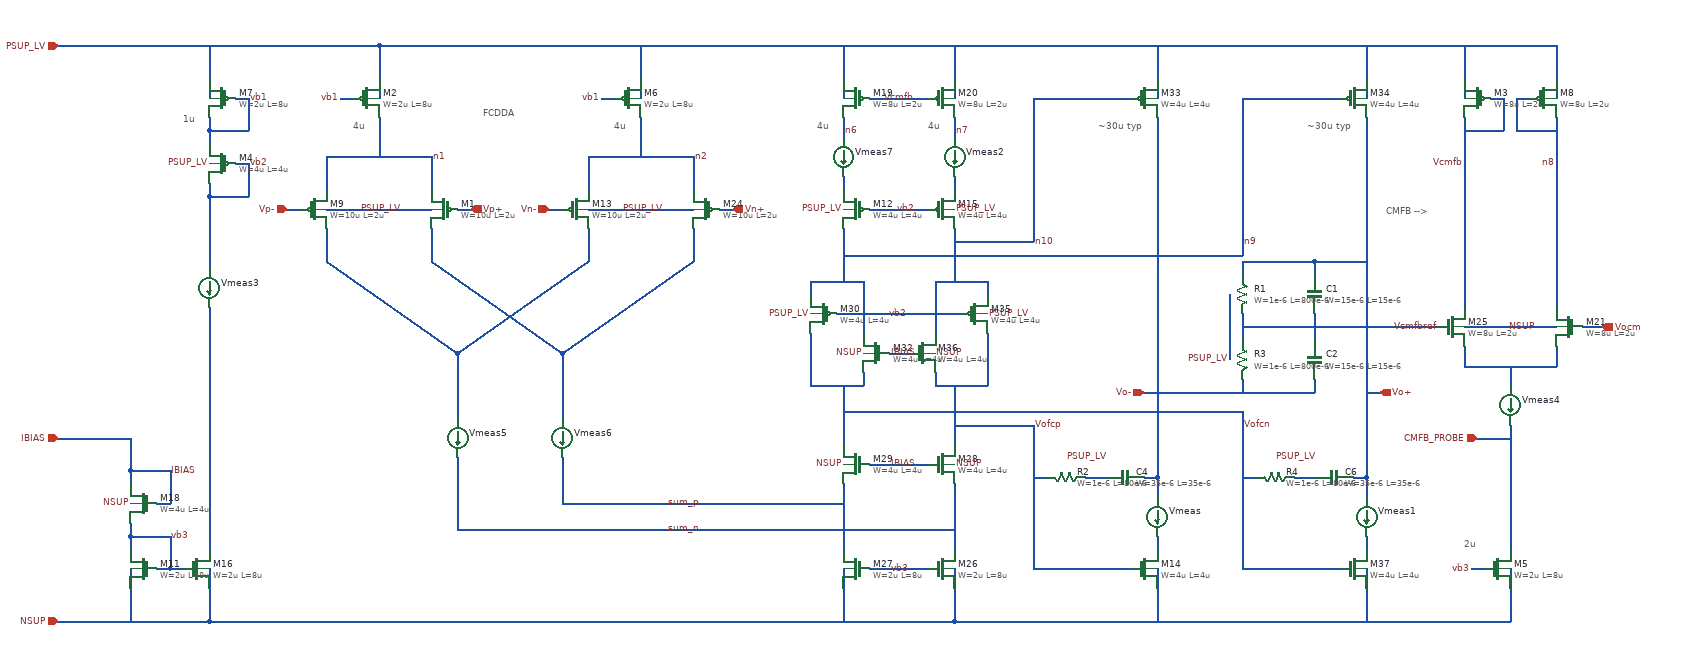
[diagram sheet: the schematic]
v {xschem version=3.4.7 file_version=1.2}
G {}
K {}
V {}
S {}
E {}
T {1u} -340 -630 0 0 0.4 0.4 {}
T {4u} -80 -620 0 0 0.4 0.4 {}
T {CMFB -->} 1500 -490 0 0 0.4 0.4 {}
T {4u} 630 -620 0 0 0.4 0.4 {}
T {4u} 800 -620 0 0 0.4 0.4 {}
T {2u} 1620 20 0 0 0.4 0.4 {}
T {FCDDA} 120 -640 0 0 0.4 0.4 {}
T {~30u typ} 1060 -620 0 0 0.4 0.4 {}
T {~30u typ} 1380 -620 0 0 0.4 0.4 {}
T {4u} 320 -620 0 0 0.4 0.4 {}
N -530 -730 -520 -730 {lab=PSUP_LV}
N -300 -680 -300 -650 {lab=PSUP_LV}
N -300 -730 -300 -680 {lab=PSUP_LV}
N -300 -600 -240 -600 {lab=vb1}
N -300 20 -300 40 {lab=#net1}
N -360 70 -340 70 {lab=vb3}
N -120 -560 -120 -510 {lab=n1}
N 40 -560 40 -510 {lab=n1}
N -40 -620 -40 -560 {lab=n1}
N -40 -730 -40 -680 {lab=PSUP_LV}
N -120 -450 -120 -400 {lab=#net2}
N 360 -680 360 -650 {lab=PSUP_LV}
N -100 -650 -80 -650 {lab=vb1}
N 300 -650 320 -650 {lab=vb1}
N 80 -480 100 -480 {lab=Vp+}
N -180 -480 -160 -480 {lab=Vp-}
N 360 -730 360 -680 {lab=PSUP_LV}
N -40 -680 -40 -650 {lab=PSUP_LV}
N -120 -560 30 -560 {lab=n1}
N 280 -560 280 -510 {lab=n2}
N 440 -560 440 -510 {lab=n2}
N 280 -560 440 -560 {lab=n2}
N 360 -620 360 -560 {lab=n2}
N 40 -450 40 -400 {lab=#net3}
N 440 -450 440 -400 {lab=#net3}
N 220 -480 240 -480 {lab=Vn-}
N 480 -480 500 -480 {lab=Vn+}
N 30 -560 40 -560 {lab=n1}
N -120 -400 80 -260 {lab=#net2}
N 80 -260 280 -400 {lab=#net2}
N 280 -480 430 -480 {lab=PSUP_LV}
N 280 -450 280 -400 {lab=#net2}
N 40 -400 240 -260 {lab=#net3}
N 240 -260 440 -400 {lab=#net3}
N 430 -480 440 -480 {lab=PSUP_LV}
N -260 -650 -240 -650 {lab=vb1}
N 710 -650 800 -650 {lab=Vcmfb}
N 710 70 800 70 {lab=vb3}
N 670 -730 670 -650 {lab=PSUP_LV}
N 840 -730 840 -650 {lab=PSUP_LV}
N -240 -650 -240 -600 {lab=vb1}
N -300 -620 -300 -600 {lab=vb1}
N -300 -500 -240 -500 {lab=vb2}
N -240 -550 -240 -500 {lab=vb2}
N -300 -520 -300 -500 {lab=vb2}
N -260 -550 -240 -550 {lab=vb2}
N -300 -600 -300 -580 {lab=vb1}
N -300 -500 -300 -450 {lab=vb2}
N 740 -90 760 -90 {lab=IBIAS}
N 710 -90 740 -90 {lab=IBIAS}
N 760 -90 800 -90 {lab=IBIAS}
N 740 -480 760 -480 {lab=vb2}
N 710 -480 740 -480 {lab=vb2}
N 760 -480 800 -480 {lab=vb2}
N 80 -100 80 -50 {lab=sum_n}
N 140 10 840 10 {lab=sum_n}
N 240 -30 610 -30 {lab=sum_p}
N 1620 -270 1620 -240 {lab=#net4}
N 1760 -270 1760 -240 {lab=#net4}
N 1620 -440 1620 -350 {lab=Vcmfb
}
N 1760 -460 1760 -400 {lab=n8}
N 1630 -300 1750 -300 {lab=NSUP}
N 1630 -240 1750 -240 {lab=#net4}
N 1660 -650 1670 -650 {lab=Vcmfb}
N 1620 -600 1670 -600 {lab=Vcmfb}
N 1710 -650 1720 -650 {lab=n8}
N 1710 -600 1760 -600 {lab=n8}
N 1670 -650 1680 -650 {lab=Vcmfb}
N 1680 -650 1680 -600 {lab=Vcmfb}
N 1670 -600 1680 -600 {lab=Vcmfb}
N 1700 -650 1710 -650 {lab=n8}
N 1700 -650 1700 -600 {lab=n8}
N 1700 -600 1710 -600 {lab=n8}
N 1620 -300 1630 -300 {lab=NSUP}
N 1750 -300 1760 -300 {lab=NSUP}
N 1620 -240 1630 -240 {lab=#net4}
N 1750 -240 1760 -240 {lab=#net4}
N 1760 -610 1760 -460 {lab=n8}
N 1620 -610 1620 -470 {lab=Vcmfb}
N 1620 -470 1620 -440 {lab=Vcmfb}
N 1760 -730 1760 -650 {lab=PSUP_LV}
N 1620 -730 1620 -650 {lab=PSUP_LV}
N 1620 -620 1620 -610 {lab=Vcmfb}
N 1760 -620 1760 -610 {lab=n8}
N 1640 -130 1690 -130 {lab=CMFB_PROBE}
N -120 -480 40 -480 {lab=PSUP_LV}
N 610 -30 670 -30 {lab=sum_p}
N -300 -450 -300 -390 {lab=vb2}
N 240 -100 240 -60 {lab=sum_p}
N 80 10 140 10 {lab=sum_n}
N 80 -20 80 10 {lab=sum_n}
N -360 20 -360 70 {lab=vb3}
N -420 20 -420 40 {lab=vb3}
N -380 70 -360 70 {lab=vb3}
N -420 20 -360 20 {lab=vb3}
N -360 -80 -360 -30 {lab=IBIAS}
N -420 -80 -420 -60 {lab=IBIAS}
N -380 -30 -360 -30 {lab=IBIAS}
N -420 -80 -360 -80 {lab=IBIAS}
N 620 -290 620 -210 {lab=Vofcn}
N 700 -220 700 -210 {lab=Vofcn}
N 700 -230 700 -220 {lab=Vofcn}
N 700 -360 700 -290 {lab=n9}
N 700 -370 700 -360 {lab=n9}
N 640 -370 700 -370 {lab=n9}
N 620 -370 620 -350 {lab=n9}
N 620 -370 640 -370 {lab=n9}
N 620 -210 640 -210 {lab=Vofcn}
N 740 -260 770 -260 {lab=IBIAS}
N 890 -290 890 -210 {lab=Vofcp}
N 810 -210 870 -210 {lab=Vofcp}
N 810 -220 810 -210 {lab=Vofcp}
N 810 -230 810 -220 {lab=Vofcp}
N 810 -360 810 -290 {lab=n10}
N 810 -370 810 -360 {lab=n10}
N 810 -370 870 -370 {lab=n10}
N 890 -370 890 -350 {lab=n10}
N 870 -370 890 -370 {lab=n10}
N 870 -210 890 -210 {lab=Vofcp}
N 640 -210 700 -210 {lab=Vofcn}
N 670 -450 670 -420 {lab=n9}
N 840 -450 840 -420 {lab=n10}
N 670 -200 670 -180 {lab=Vofcn}
N 660 -320 850 -320 {lab=vb2}
N -420 0 -420 20 {lab=vb3}
N 670 -380 670 -370 {lab=n9}
N 840 -380 840 -370 {lab=n10}
N 1150 -730 1150 -650 {lab=PSUP_LV}
N 1470 -730 1470 -650 {lab=PSUP_LV}
N 1150 70 1150 100 {lab=NSUP}
N 1470 70 1470 100 {lab=NSUP}
N 670 -180 670 -160 {lab=Vofcn}
N 670 -420 670 -380 {lab=n9}
N 840 -420 840 -380 {lab=n10}
N 840 -430 960 -430 {lab=n10}
N 960 -650 960 -430 {lab=n10}
N 1000 -650 1110 -650 {lab=n10}
N 1280 -650 1280 -430 {lab=n9}
N 1320 -650 1430 -650 {lab=n9}
N -420 -100 -420 -80 {lab=IBIAS}
N -300 0 -300 20 {lab=#net1}
N -420 100 -420 150 {lab=NSUP}
N -300 100 -300 150 {lab=NSUP}
N 840 100 840 150 {lab=NSUP}
N 840 70 840 100 {lab=NSUP}
N 670 70 670 150 {lab=NSUP}
N 670 20 670 40 {lab=sum_p}
N 840 20 840 40 {lab=sum_n}
N 240 -60 240 -40 {lab=sum_p}
N 80 -40 80 -20 {lab=sum_n}
N 670 -60 670 20 {lab=sum_p}
N 670 -160 670 -120 {lab=Vofcn}
N 840 -160 840 -120 {lab=Vofcp}
N 1150 100 1150 150 {lab=NSUP}
N 1470 100 1470 150 {lab=NSUP}
N 1470 -620 1470 -600 {lab=Vo+}
N 80 -50 80 -40 {lab=sum_n}
N 240 -40 240 -30 {lab=sum_p}
N 840 -150 960 -150 {lab=Vofcp}
N 960 -150 960 70 {lab=Vofcp}
N 1000 70 1110 70 {lab=Vofcp}
N 670 -210 670 -200 {lab=Vofcn}
N 240 -260 240 -250 {lab=#net3}
N 80 -260 80 -250 {lab=#net2}
N 1280 40 1280 70 {lab=Vofcn}
N 1320 70 1430 70 {lab=Vofcn}
N 1470 -600 1470 -590 {lab=Vo+}
N 1150 -620 1150 -610 {lab=Vo-}
N -300 70 -300 100 {lab=NSUP}
N -420 70 -420 100 {lab=NSUP}
N 670 -410 910 -410 {lab=n9}
N 840 -210 840 -160 {lab=Vofcp}
N 670 -170 910 -170 {lab=Vofcn}
N 840 150 880 150 {lab=NSUP}
N 960 70 1000 70 {lab=Vofcp}
N 910 -170 950 -170 {lab=Vofcn}
N 910 -410 950 -410 {lab=n9}
N 960 -650 1000 -650 {lab=n10}
N 1000 -410 1280 -410 {lab=n9}
N 1000 -170 1280 -170 {lab=Vofcn}
N 1280 -650 1320 -650 {lab=n9}
N 1280 70 1320 70 {lab=Vofcn}
N 1130 -200 1150 -200 {lab=Vo-}
N 1470 -200 1490 -200 {lab=Vo+}
N 1660 -730 1720 -730 {lab=PSUP_LV}
N 1650 -730 1660 -730 {lab=PSUP_LV}
N 1800 -300 1830 -300 {lab=Vocm}
N 1720 -730 1760 -730 {lab=PSUP_LV}
N 1150 -200 1190 -200 {lab=Vo-}
N 880 150 920 150 {lab=NSUP}
N 1690 20 1690 40 {lab=CMFB_PROBE}
N 1630 70 1650 70 {lab=vb3}
N 1690 -80 1690 -60 {lab=CMFB_PROBE}
N 1690 0 1690 20 {lab=CMFB_PROBE}
N 1690 100 1690 150 {lab=NSUP}
N 1690 70 1690 100 {lab=NSUP}
N 1690 -140 1690 -80 {lab=CMFB_PROBE}
N 1400 -400 1470 -400 {lab=Vo+}
N 1280 -170 1280 40 {lab=Vofcn}
N 1280 -430 1280 -410 {lab=n9}
N 1760 -400 1760 -330 {lab=n8}
N 1620 -350 1620 -330 {lab=Vcmfb}
N 1560 -300 1580 -300 {lab=Vcmfbref}
N 1690 -240 1690 -230 {lab=#net4}
N 1330 -300 1560 -300 {lab=Vcmfbref}
N 970 150 1690 150 {lab=NSUP}
N 1570 -730 1650 -730 {lab=PSUP_LV}
N 840 0 840 20 {lab=sum_n}
N 840 -60 840 0 {lab=sum_n}
N 920 150 970 150 {lab=NSUP}
N 950 -170 1000 -170 {lab=Vofcn}
N 1190 -200 1240 -200 {lab=Vo-}
N 950 -410 1000 -410 {lab=n9}
N 1150 20 1150 40 {lab=#net5}
N 1130 -70 1150 -70 {lab=Vo-}
N 1450 -70 1470 -70 {lab=Vo+}
N 690 150 840 150 {lab=NSUP}
N 1280 -310 1280 -280 {lab=Vcmfbref}
N 1280 -320 1280 -310 {lab=Vcmfbref}
N 1280 -300 1310 -300 {lab=Vcmfbref}
N 1390 -320 1390 -280 {lab=Vcmfbref}
N 1390 -320 1390 -300 {lab=Vcmfbref}
N 1280 -400 1280 -380 {lab=Vo+}
N 1290 -400 1390 -400 {lab=Vo+}
N 1390 -400 1390 -380 {lab=Vo+}
N 1390 -220 1390 -200 {lab=Vo-}
N 1280 -220 1280 -200 {lab=Vo-}
N 1260 -350 1260 -250 {lab=PSUP_LV}
N 1310 -300 1320 -300 {lab=Vcmfbref}
N 1280 -400 1290 -400 {lab=Vo+}
N 1240 -200 1390 -200 {lab=Vo-}
N 1320 -300 1330 -300 {lab=Vcmfbref}
N 1390 -400 1400 -400 {lab=Vo+}
N -300 -200 -300 0 {lab=#net1}
N -460 -130 -420 -130 {lab=IBIAS}
N -500 150 -300 150 {lab=NSUP}
N -40 -730 1570 -730 {lab=PSUP_LV}
N 1150 -610 1150 -70 {lab=Vo-}
N 1150 -70 1150 -40 {lab=Vo-}
N 1470 -590 1470 -70 {lab=Vo+}
N 1470 20 1470 40 {lab=#net6}
N 1470 -70 1470 -40 {lab=Vo+}
N -420 -130 -420 -100 {lab=IBIAS}
N -530 -130 -460 -130 {lab=IBIAS}
N -530 150 -500 150 {lab=NSUP}
N -520 -730 -260 -730 {lab=PSUP_LV}
N -260 -730 -40 -730 {lab=PSUP_LV}
N -300 150 690 150 {lab=NSUP}
N 1040 -70 1070 -70 {lab=Vofcp}
N 1360 -70 1390 -70 {lab=Vofcn}
N 840 -620 840 -590 {lab=n7}
N 840 -530 840 -510 {lab=#net7}
N -300 -330 -300 -200 {lab=#net1}
N 1690 -150 1690 -140 {lab=CMFB_PROBE}
N 1690 -230 1690 -210 {lab=#net4}
N 1690 -60 1690 0 {lab=CMFB_PROBE}
N 240 -250 240 -160 {lab=#net3}
N 80 -250 80 -160 {lab=#net2}
N 670 -530 670 -510 {lab=#net8}
N 670 -620 670 -590 {lab=n6}
N 960 -70 980 -70 {lab=Vofcp}
N 1280 -70 1300 -70 {lab=Vofcn}
C {ipin.sym} -530 -730 0 0 {name=p19 lab=PSUP_LV
}
C {ipin.sym} -530 150 0 0 {name=p20 lab=NSUP
}
C {ipin.sym} -530 -130 0 0 {name=p9 lab=IBIAS


}
C {symbols/pfet_03v3.sym} -280 -650 0 1 {name=M7
L=8u
W=2u
nf=1
m=4
ad="'int((nf+1)/2) * W/nf * 0.18u'"
pd="'2*int((nf+1)/2) * (W/nf + 0.18u)'"
as="'int((nf+2)/2) * W/nf * 0.18u'"
ps="'2*int((nf+2)/2) * (W/nf + 0.18u)'"
nrd="'0.18u / W'" nrs="'0.18u / W'"
sa=0 sb=0 sd=0
model=pfet_03v3
spiceprefix=X
}
C {lab_pin.sym} -240 -650 0 1 {name=p8 sig_type=std_logic lab=vb1}
C {symbols/nfet_03v3.sym} -320 70 0 0 {name=M16
L=8u
W=2u
nf=1
m=4
ad="'int((nf+1)/2) * W/nf * 0.18u'"
pd="'2*int((nf+1)/2) * (W/nf + 0.18u)'"
as="'int((nf+2)/2) * W/nf * 0.18u'"
ps="'2*int((nf+2)/2) * (W/nf + 0.18u)'"
nrd="'0.18u / W'" nrs="'0.18u / W'"
sa=0 sb=0 sd=0
model=nfet_03v3
spiceprefix=X
}
C {lab_pin.sym} -360 20 2 0 {name=p29 sig_type=std_logic lab=vb3}
C {symbols/pfet_03v3.sym} -140 -480 0 0 {name=M9
L=2u
W=10u
nf=1
m=40
ad="'int((nf+1)/2) * W/nf * 0.18u'"
pd="'2*int((nf+1)/2) * (W/nf + 0.18u)'"
as="'int((nf+2)/2) * W/nf * 0.18u'"
ps="'2*int((nf+2)/2) * (W/nf + 0.18u)'"
nrd="'0.18u / W'" nrs="'0.18u / W'"
sa=0 sb=0 sd=0
model=pfet_03v3
spiceprefix=X
}
C {symbols/pfet_03v3.sym} 60 -480 0 1 {name=M1
L=2u
W=10u
nf=1
m=40
ad="'int((nf+1)/2) * W/nf * 0.18u'"
pd="'2*int((nf+1)/2) * (W/nf + 0.18u)'"
as="'int((nf+2)/2) * W/nf * 0.18u'"
ps="'2*int((nf+2)/2) * (W/nf + 0.18u)'"
nrd="'0.18u / W'" nrs="'0.18u / W'"
sa=0 sb=0 sd=0
model=pfet_03v3
spiceprefix=X
}
C {lab_pin.sym} -70 -480 2 0 {name=p6 sig_type=std_logic lab=PSUP_LV}
C {symbols/pfet_03v3.sym} -60 -650 0 0 {name=M2
L=8u
W=2u
nf=1
m=16
ad="'int((nf+1)/2) * W/nf * 0.18u'"
pd="'2*int((nf+1)/2) * (W/nf + 0.18u)'"
as="'int((nf+2)/2) * W/nf * 0.18u'"
ps="'2*int((nf+2)/2) * (W/nf + 0.18u)'"
nrd="'0.18u / W'" nrs="'0.18u / W'"
sa=0 sb=0 sd=0
model=pfet_03v3
spiceprefix=X
}
C {symbols/pfet_03v3.sym} 340 -650 0 0 {name=M6
L=8u
W=2u
nf=1
m=16
ad="'int((nf+1)/2) * W/nf * 0.18u'"
pd="'2*int((nf+1)/2) * (W/nf + 0.18u)'"
as="'int((nf+2)/2) * W/nf * 0.18u'"
ps="'2*int((nf+2)/2) * (W/nf + 0.18u)'"
nrd="'0.18u / W'" nrs="'0.18u / W'"
sa=0 sb=0 sd=0
model=pfet_03v3
spiceprefix=X
}
C {lab_pin.sym} -100 -650 0 0 {name=p16 sig_type=std_logic lab=vb1}
C {lab_pin.sym} 300 -650 0 0 {name=p17 sig_type=std_logic lab=vb1}
C {ipin.sym} 100 -480 0 1 {name=p23 lab=Vp+

}
C {ipin.sym} -180 -480 0 0 {name=p24 lab=Vp-

}
C {ipin.sym} 500 -480 0 1 {name=p25 lab=Vn+

}
C {ipin.sym} 220 -480 0 0 {name=p26 lab=Vn-

}
C {lab_pin.sym} 40 -560 2 0 {name=p11 sig_type=std_logic lab=n1}
C {lab_pin.sym} 440 -560 2 0 {name=p14 sig_type=std_logic lab=n2}
C {symbols/pfet_03v3.sym} 460 -480 0 1 {name=M24
L=2u
W=10u
nf=1
m=40
ad="'int((nf+1)/2) * W/nf * 0.18u'"
pd="'2*int((nf+1)/2) * (W/nf + 0.18u)'"
as="'int((nf+2)/2) * W/nf * 0.18u'"
ps="'2*int((nf+2)/2) * (W/nf + 0.18u)'"
nrd="'0.18u / W'" nrs="'0.18u / W'"
sa=0 sb=0 sd=0
model=pfet_03v3
spiceprefix=X
}
C {lab_pin.sym} 330 -480 2 0 {name=p28 sig_type=std_logic lab=PSUP_LV}
C {symbols/pfet_03v3.sym} 260 -480 0 0 {name=M13
L=2u
W=10u
nf=1
m=40
ad="'int((nf+1)/2) * W/nf * 0.18u'"
pd="'2*int((nf+1)/2) * (W/nf + 0.18u)'"
as="'int((nf+2)/2) * W/nf * 0.18u'"
ps="'2*int((nf+2)/2) * (W/nf + 0.18u)'"
nrd="'0.18u / W'" nrs="'0.18u / W'"
sa=0 sb=0 sd=0
model=pfet_03v3
spiceprefix=X
}
C {symbols/pfet_03v3.sym} 690 -480 0 1 {name=M12
L=4u
W=4u
nf=1
m=30
ad="'int((nf+1)/2) * W/nf * 0.18u'"
pd="'2*int((nf+1)/2) * (W/nf + 0.18u)'"
as="'int((nf+2)/2) * W/nf * 0.18u'"
ps="'2*int((nf+2)/2) * (W/nf + 0.18u)'"
nrd="'0.18u / W'" nrs="'0.18u / W'"
sa=0 sb=0 sd=0
model=pfet_03v3
spiceprefix=X
}
C {symbols/pfet_03v3.sym} 820 -480 0 0 {name=M15
L=4u
W=4u
nf=1
m=30
ad="'int((nf+1)/2) * W/nf * 0.18u'"
pd="'2*int((nf+1)/2) * (W/nf + 0.18u)'"
as="'int((nf+2)/2) * W/nf * 0.18u'"
ps="'2*int((nf+2)/2) * (W/nf + 0.18u)'"
nrd="'0.18u / W'" nrs="'0.18u / W'"
sa=0 sb=0 sd=0
model=pfet_03v3
spiceprefix=X
}
C {lab_pin.sym} 670 -480 2 1 {name=p34 sig_type=std_logic lab=PSUP_LV}
C {symbols/pfet_03v3.sym} 690 -650 0 1 {name=M19
L=2u
W=8u
nf=1
m=16
ad="'int((nf+1)/2) * W/nf * 0.18u'"
pd="'2*int((nf+1)/2) * (W/nf + 0.18u)'"
as="'int((nf+2)/2) * W/nf * 0.18u'"
ps="'2*int((nf+2)/2) * (W/nf + 0.18u)'"
nrd="'0.18u / W'" nrs="'0.18u / W'"
sa=0 sb=0 sd=0
model=pfet_03v3
spiceprefix=X
}
C {symbols/pfet_03v3.sym} 820 -650 0 0 {name=M20
L=2u
W=8u
nf=1
m=16
ad="'int((nf+1)/2) * W/nf * 0.18u'"
pd="'2*int((nf+1)/2) * (W/nf + 0.18u)'"
as="'int((nf+2)/2) * W/nf * 0.18u'"
ps="'2*int((nf+2)/2) * (W/nf + 0.18u)'"
nrd="'0.18u / W'" nrs="'0.18u / W'"
sa=0 sb=0 sd=0
model=pfet_03v3
spiceprefix=X
}
C {lab_pin.sym} 840 -480 2 0 {name=p37 sig_type=std_logic lab=PSUP_LV}
C {symbols/nfet_03v3.sym} 820 70 0 0 {name=M26
L=8u
W=2u
nf=1
m=32
ad="'int((nf+1)/2) * W/nf * 0.18u'"
pd="'2*int((nf+1)/2) * (W/nf + 0.18u)'"
as="'int((nf+2)/2) * W/nf * 0.18u'"
ps="'2*int((nf+2)/2) * (W/nf + 0.18u)'"
nrd="'0.18u / W'" nrs="'0.18u / W'"
sa=0 sb=0 sd=0
model=nfet_03v3
spiceprefix=X
}
C {lab_pin.sym} 780 -650 0 0 {name=p39 sig_type=std_logic lab=Vcmfb}
C {lab_pin.sym} 740 70 2 0 {name=p38 sig_type=std_logic lab=vb3}
C {symbols/nfet_03v3.sym} 690 70 0 1 {name=M27
L=8u
W=2u
nf=1
m=32
ad="'int((nf+1)/2) * W/nf * 0.18u'"
pd="'2*int((nf+1)/2) * (W/nf + 0.18u)'"
as="'int((nf+2)/2) * W/nf * 0.18u'"
ps="'2*int((nf+2)/2) * (W/nf + 0.18u)'"
nrd="'0.18u / W'" nrs="'0.18u / W'"
sa=0 sb=0 sd=0
model=nfet_03v3
spiceprefix=X
}
C {symbols/nfet_03v3.sym} 820 -90 0 0 {name=M28
L=4u
W=4u
nf=1
m=10
ad="'int((nf+1)/2) * W/nf * 0.18u'"
pd="'2*int((nf+1)/2) * (W/nf + 0.18u)'"
as="'int((nf+2)/2) * W/nf * 0.18u'"
ps="'2*int((nf+2)/2) * (W/nf + 0.18u)'"
nrd="'0.18u / W'" nrs="'0.18u / W'"
sa=0 sb=0 sd=0
model=nfet_03v3
spiceprefix=X
}
C {symbols/nfet_03v3.sym} 690 -90 0 1 {name=M29
L=4u
W=4u
nf=1
m=10
ad="'int((nf+1)/2) * W/nf * 0.18u'"
pd="'2*int((nf+1)/2) * (W/nf + 0.18u)'"
as="'int((nf+2)/2) * W/nf * 0.18u'"
ps="'2*int((nf+2)/2) * (W/nf + 0.18u)'"
nrd="'0.18u / W'" nrs="'0.18u / W'"
sa=0 sb=0 sd=0
model=nfet_03v3
spiceprefix=X
}
C {lab_pin.sym} 400 -30 2 0 {name=p41 sig_type=std_logic lab=sum_p}
C {lab_pin.sym} 400 10 2 0 {name=p43 sig_type=std_logic lab=sum_n}
C {lab_pin.sym} 670 -90 2 1 {name=p50 sig_type=std_logic lab=NSUP}
C {lab_pin.sym} 840 -90 2 0 {name=p51 sig_type=std_logic lab=NSUP}
C {symbols/pfet_03v3.sym} 1640 -650 0 1 {name=M3
L=2u
W=8u
nf=1
m=4
ad="'int((nf+1)/2) * W/nf * 0.18u'"
pd="'2*int((nf+1)/2) * (W/nf + 0.18u)'"
as="'int((nf+2)/2) * W/nf * 0.18u'"
ps="'2*int((nf+2)/2) * (W/nf + 0.18u)'"
nrd="'0.18u / W'" nrs="'0.18u / W'"
sa=0 sb=0 sd=0
model=pfet_03v3
spiceprefix=X
}
C {symbols/pfet_03v3.sym} 1740 -650 0 0 {name=M8
L=2u
W=8u
nf=1
m=4
ad="'int((nf+1)/2) * W/nf * 0.18u'"
pd="'2*int((nf+1)/2) * (W/nf + 0.18u)'"
as="'int((nf+2)/2) * W/nf * 0.18u'"
ps="'2*int((nf+2)/2) * (W/nf + 0.18u)'"
nrd="'0.18u / W'" nrs="'0.18u / W'"
sa=0 sb=0 sd=0
model=pfet_03v3
spiceprefix=X
}
C {lab_pin.sym} 1730 -300 0 0 {name=p52 sig_type=std_logic lab=NSUP}
C {symbols/nfet_03v3.sym} 1780 -300 0 1 {name=M21
L=2u
W=8u
nf=1
m=8
ad="'int((nf+1)/2) * W/nf * 0.18u'"
pd="'2*int((nf+1)/2) * (W/nf + 0.18u)'"
as="'int((nf+2)/2) * W/nf * 0.18u'"
ps="'2*int((nf+2)/2) * (W/nf + 0.18u)'"
nrd="'0.18u / W'" nrs="'0.18u / W'"
sa=0 sb=0 sd=0
model=nfet_03v3
spiceprefix=X
}
C {symbols/nfet_03v3.sym} 1600 -300 0 0 {name=M25
L=2u
W=8u
nf=1
m=8
ad="'int((nf+1)/2) * W/nf * 0.18u'"
pd="'2*int((nf+1)/2) * (W/nf + 0.18u)'"
as="'int((nf+2)/2) * W/nf * 0.18u'"
ps="'2*int((nf+2)/2) * (W/nf + 0.18u)'"
nrd="'0.18u / W'" nrs="'0.18u / W'"
sa=0 sb=0 sd=0
model=nfet_03v3
spiceprefix=X
}
C {lab_pin.sym} 1620 -550 0 0 {name=p1 sig_type=std_logic lab=Vcmfb}
C {lab_pin.sym} 670 -600 2 0 {name=p35 sig_type=std_logic lab=n6}
C {lab_pin.sym} 840 -600 2 0 {name=p36 sig_type=std_logic lab=n7}
C {lab_pin.sym} 1260 -250 2 1 {name=p53 sig_type=std_logic lab=PSUP_LV}
C {ipin.sym} 1640 -130 0 0 {name=p2 lab=CMFB_PROBE


}
C {gf180mcu_fd_pr/cap_mim_2f0fF.sym} 1390 -350 2 1 {name=C1
W=15e-6
L=15e-6
model=cap_mim_2f0fF
spiceprefix=X
m=1
}
C {gf180mcu_fd_pr/cap_mim_2f0fF.sym} 1390 -250 2 1 {name=C2
W=15e-6
L=15e-6
model=cap_mim_2f0fF
spiceprefix=X
m=1
}
C {lab_pin.sym} 750 -480 2 0 {name=p4 sig_type=std_logic lab=vb2}
C {lab_pin.sym} -240 -550 2 0 {name=p5 sig_type=std_logic lab=vb2}
C {symbols/nfet_03v3.sym} -400 70 0 1 {name=M11
L=8u
W=2u
nf=1
m=4
ad="'int((nf+1)/2) * W/nf * 0.18u'"
pd="'2*int((nf+1)/2) * (W/nf + 0.18u)'"
as="'int((nf+2)/2) * W/nf * 0.18u'"
ps="'2*int((nf+2)/2) * (W/nf + 0.18u)'"
nrd="'0.18u / W'" nrs="'0.18u / W'"
sa=0 sb=0 sd=0
model=nfet_03v3
spiceprefix=X
}
C {symbols/nfet_03v3.sym} -400 -30 0 1 {name=M18
L=4u
W=4u
nf=1
m=4
ad="'int((nf+1)/2) * W/nf * 0.18u'"
pd="'2*int((nf+1)/2) * (W/nf + 0.18u)'"
as="'int((nf+2)/2) * W/nf * 0.18u'"
ps="'2*int((nf+2)/2) * (W/nf + 0.18u)'"
nrd="'0.18u / W'" nrs="'0.18u / W'"
sa=0 sb=0 sd=0
model=nfet_03v3
spiceprefix=X
}
C {lab_pin.sym} -360 -80 2 0 {name=p33 sig_type=std_logic lab=IBIAS}
C {lab_pin.sym} -420 -30 0 0 {name=p32 sig_type=std_logic lab=NSUP}
C {lab_pin.sym} 620 -320 2 1 {name=p30 sig_type=std_logic lab=PSUP_LV}
C {lab_pin.sym} 700 -260 2 1 {name=p44 sig_type=std_logic lab=NSUP}
C {symbols/pfet_03v3.sym} 640 -320 0 1 {name=M30
L=4u
W=4u
nf=1
m=16
ad="'int((nf+1)/2) * W/nf * 0.18u'"
pd="'2*int((nf+1)/2) * (W/nf + 0.18u)'"
as="'int((nf+2)/2) * W/nf * 0.18u'"
ps="'2*int((nf+2)/2) * (W/nf + 0.18u)'"
nrd="'0.18u / W'" nrs="'0.18u / W'"
sa=0 sb=0 sd=0
model=pfet_03v3
spiceprefix=X
}
C {symbols/nfet_03v3.sym} 720 -260 0 1 {name=M32
L=4u
W=4u
nf=1
m=8
ad="'int((nf+1)/2) * W/nf * 0.18u'"
pd="'2*int((nf+1)/2) * (W/nf + 0.18u)'"
as="'int((nf+2)/2) * W/nf * 0.18u'"
ps="'2*int((nf+2)/2) * (W/nf + 0.18u)'"
nrd="'0.18u / W'" nrs="'0.18u / W'"
sa=0 sb=0 sd=0
model=nfet_03v3
spiceprefix=X
}
C {lab_pin.sym} 890 -320 2 0 {name=p59 sig_type=std_logic lab=PSUP_LV}
C {lab_pin.sym} 810 -260 2 0 {name=p60 sig_type=std_logic lab=NSUP}
C {symbols/pfet_03v3.sym} 870 -320 0 0 {name=M35
L=4u
W=4u
nf=1
m=16
ad="'int((nf+1)/2) * W/nf * 0.18u'"
pd="'2*int((nf+1)/2) * (W/nf + 0.18u)'"
as="'int((nf+2)/2) * W/nf * 0.18u'"
ps="'2*int((nf+2)/2) * (W/nf + 0.18u)'"
nrd="'0.18u / W'" nrs="'0.18u / W'"
sa=0 sb=0 sd=0
model=pfet_03v3
spiceprefix=X
}
C {symbols/nfet_03v3.sym} 790 -260 0 0 {name=M36
L=4u
W=4u
nf=1
m=8
ad="'int((nf+1)/2) * W/nf * 0.18u'"
pd="'2*int((nf+1)/2) * (W/nf + 0.18u)'"
as="'int((nf+2)/2) * W/nf * 0.18u'"
ps="'2*int((nf+2)/2) * (W/nf + 0.18u)'"
nrd="'0.18u / W'" nrs="'0.18u / W'"
sa=0 sb=0 sd=0
model=nfet_03v3
spiceprefix=X
}
C {lab_pin.sym} 770 -320 0 0 {name=p45 sig_type=std_logic lab=vb2}
C {symbols/nfet_03v3.sym} 1130 70 0 0 {name=M14
L=4u
W=4u
nf=1
m=16
ad="'int((nf+1)/2) * W/nf * 0.18u'"
pd="'2*int((nf+1)/2) * (W/nf + 0.18u)'"
as="'int((nf+2)/2) * W/nf * 0.18u'"
ps="'2*int((nf+2)/2) * (W/nf + 0.18u)'"
nrd="'0.18u / W'" nrs="'0.18u / W'"
sa=0 sb=0 sd=0
model=nfet_03v3
spiceprefix=X
}
C {symbols/nfet_03v3.sym} 1450 70 0 0 {name=M37
L=4u
W=4u
nf=1
m=16
ad="'int((nf+1)/2) * W/nf * 0.18u'"
pd="'2*int((nf+1)/2) * (W/nf + 0.18u)'"
as="'int((nf+2)/2) * W/nf * 0.18u'"
ps="'2*int((nf+2)/2) * (W/nf + 0.18u)'"
nrd="'0.18u / W'" nrs="'0.18u / W'"
sa=0 sb=0 sd=0
model=nfet_03v3
spiceprefix=X
}
C {symbols/pfet_03v3.sym} 1130 -650 0 0 {name=M33
L=4u
W=4u
nf=1
m=32
ad="'int((nf+1)/2) * W/nf * 0.18u'"
pd="'2*int((nf+1)/2) * (W/nf + 0.18u)'"
as="'int((nf+2)/2) * W/nf * 0.18u'"
ps="'2*int((nf+2)/2) * (W/nf + 0.18u)'"
nrd="'0.18u / W'" nrs="'0.18u / W'"
sa=0 sb=0 sd=0
model=pfet_03v3
spiceprefix=X
}
C {symbols/pfet_03v3.sym} 1450 -650 0 0 {name=M34
L=4u
W=4u
nf=1
m=32
ad="'int((nf+1)/2) * W/nf * 0.18u'"
pd="'2*int((nf+1)/2) * (W/nf + 0.18u)'"
as="'int((nf+2)/2) * W/nf * 0.18u'"
ps="'2*int((nf+2)/2) * (W/nf + 0.18u)'"
nrd="'0.18u / W'" nrs="'0.18u / W'"
sa=0 sb=0 sd=0
model=pfet_03v3
spiceprefix=X
}
C {opin.sym} 1130 -200 0 1 {name=p27 lab=Vo-
}
C {lab_pin.sym} 960 -430 0 1 {name=p42 sig_type=std_logic lab=n10}
C {lab_pin.sym} 960 -150 2 0 {name=p66 sig_type=std_logic lab=Vofcp}
C {lab_pin.sym} 1280 -150 2 0 {name=p67 sig_type=std_logic lab=Vofcn}
C {opin.sym} 1490 -200 0 0 {name=p7 lab=Vo+
}
C {lab_pin.sym} 1580 -300 0 0 {name=p13 sig_type=std_logic lab=Vcmfbref}
C {lab_pin.sym} 1760 -550 0 0 {name=p10 sig_type=std_logic lab=n8}
C {symbols/nfet_03v3.sym} 1670 70 0 0 {name=M5
L=8u
W=2u
nf=1
m=8
ad="'int((nf+1)/2) * W/nf * 0.18u'"
pd="'2*int((nf+1)/2) * (W/nf + 0.18u)'"
as="'int((nf+2)/2) * W/nf * 0.18u'"
ps="'2*int((nf+2)/2) * (W/nf + 0.18u)'"
nrd="'0.18u / W'" nrs="'0.18u / W'"
sa=0 sb=0 sd=0
model=nfet_03v3
spiceprefix=X
}
C {lab_pin.sym} 1630 70 2 1 {name=p15 sig_type=std_logic lab=vb3}
C {lab_pin.sym} 1280 -430 0 1 {name=p40 sig_type=std_logic lab=n9}
C {gf180mcu_fd_pr/cap_mim_2f0fF.sym} 1100 -70 3 1 {name=C4
W=35e-6
L=35e-6
model=cap_mim_2f0fF
spiceprefix=X
m=1
}
C {lab_pin.sym} 1010 -100 0 1 {name=p56 sig_type=std_logic lab=PSUP_LV
L=100e-6}
C {lab_pin.sym} 1330 -100 0 1 {name=p57 sig_type=std_logic lab=PSUP_LV
L=100e-6}
C {gf180mcu_fd_pr/cap_mim_2f0fF.sym} 1420 -70 3 1 {name=C6
W=35e-6
L=35e-6
model=cap_mim_2f0fF
spiceprefix=X
m=1
}
C {symbols/pfet_03v3.sym} -280 -550 0 1 {name=M4
L=4u
W=4u
nf=1
m=8
ad="'int((nf+1)/2) * W/nf * 0.18u'"
pd="'2*int((nf+1)/2) * (W/nf + 0.18u)'"
as="'int((nf+2)/2) * W/nf * 0.18u'"
ps="'2*int((nf+2)/2) * (W/nf + 0.18u)'"
nrd="'0.18u / W'" nrs="'0.18u / W'"
sa=0 sb=0 sd=0
model=pfet_03v3
spiceprefix=X
}
C {lab_pin.sym} -300 -550 2 1 {name=p46 sig_type=std_logic lab=PSUP_LV}
C {ammeter.sym} 1150 -10 0 0 {name=Vmeas savecurrent=true spice_ignore=0}
C {ammeter.sym} 1470 -10 0 0 {name=Vmeas1 savecurrent=true spice_ignore=0}
C {ipin.sym} 1830 -300 0 1 {name=p3 lab=Vocm}
C {lab_pin.sym} 740 -90 2 0 {name=p18 sig_type=std_logic lab=IBIAS}
C {lab_pin.sym} 740 -260 2 0 {name=p21 sig_type=std_logic lab=IBIAS}
C {symbols/ppolyf_u_1k.sym} 1280 -250 0 0 {name=R3
W=1e-6
L=800e-6
model=ppolyf_u_1k
spiceprefix=X
m=1}
C {symbols/ppolyf_u_1k.sym} 1280 -350 0 0 {name=R1
W=1e-6
L=800e-6
model=ppolyf_u_1k
spiceprefix=X
m=1}
C {symbols/ppolyf_u_1k.sym} 1010 -70 1 0 {name=R2
W=1e-6
L=80e-6
model=ppolyf_u_1k
spiceprefix=X
m=1
spice_ignore=short}
C {symbols/ppolyf_u_1k.sym} 1330 -70 1 0 {name=R4
W=1e-6
L=80e-6
model=ppolyf_u_1k
spiceprefix=X
m=1
spice_ignore=short}
C {ammeter.sym} 840 -560 0 0 {name=Vmeas2 savecurrent=true spice_ignore=0}
C {ammeter.sym} -300 -360 0 0 {name=Vmeas3 savecurrent=true spice_ignore=0}
C {ammeter.sym} 1690 -180 0 0 {name=Vmeas4 savecurrent=true spice_ignore=0}
C {ammeter.sym} 80 -130 0 0 {name=Vmeas5 savecurrent=true spice_ignore=0}
C {ammeter.sym} 240 -130 0 0 {name=Vmeas6 savecurrent=true spice_ignore=0}
C {ammeter.sym} 670 -560 0 0 {name=Vmeas7 savecurrent=true spice_ignore=0}
